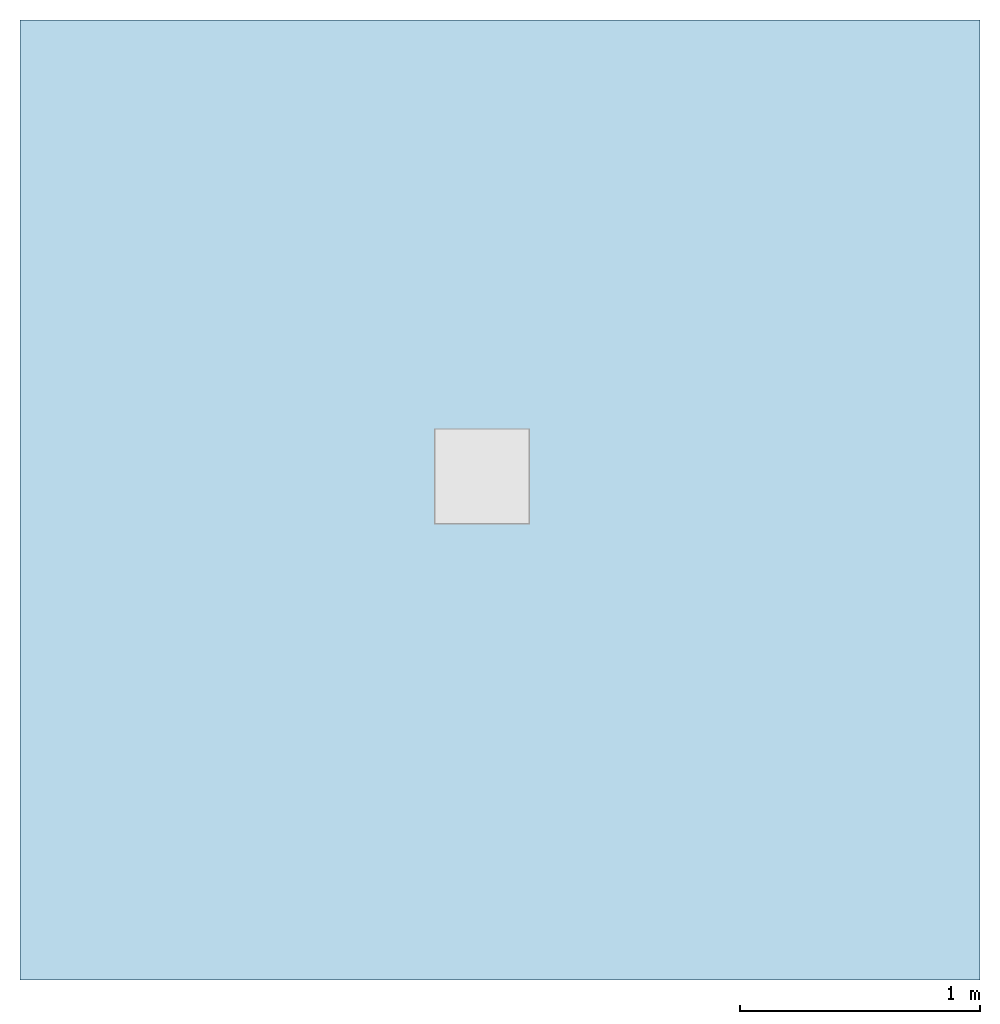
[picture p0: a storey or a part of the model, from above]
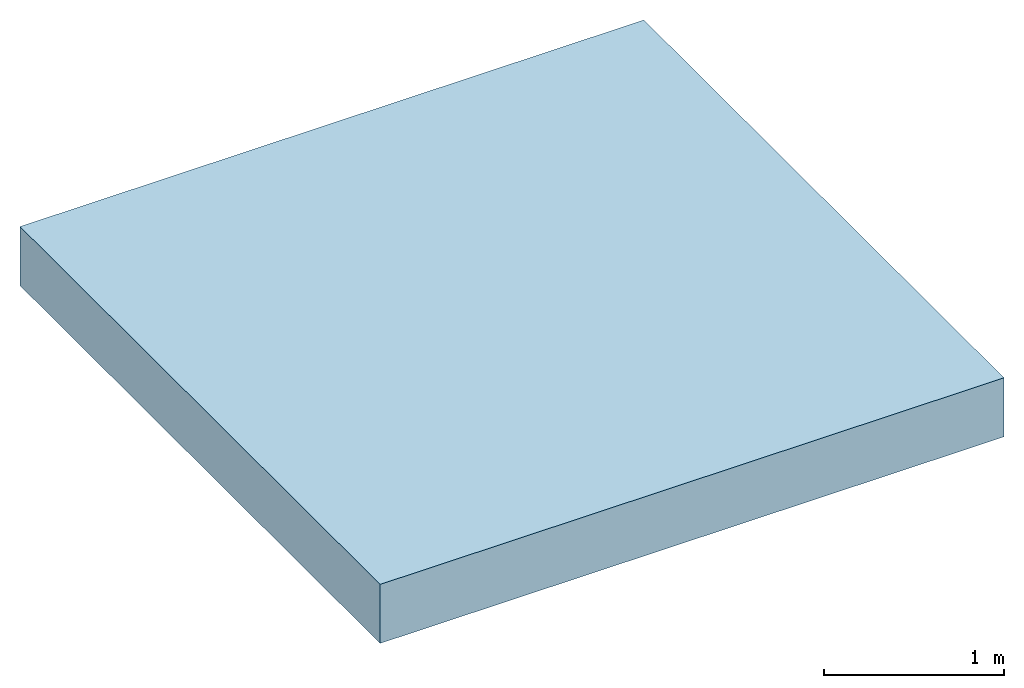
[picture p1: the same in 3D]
Properties of the parts of a building model (IFC2X3)

# File
Description: ViewDefinition [CoordinationView]
File name: Project Number
Time: 2014-06-06T11:08:49
Written by: The EXPRESS Data Manager Version 5.01.0100.02.64mod : 6 Jun 2012
Made in: 20130308_1515(x64) - Exporter 2014.0.2013.0308 - Default UI
Comment: STEP Physical File produced by: The EXPRESS Data Manager Version 5.01.0100.02.64mod : 6 Jun 2012 * Module: EDMstepFileFactory/EDMstandAlone * Creation date: Fri Jun 06 11:08:49 2014 * Host: IN-BLR-PC-0010 * Database: C:\Users\palleri\AppData\Local\Temp\{F4588F36-7AED-4A79-A1F6-AAA9ACE06403}\ifc * Database version: 5507 * Database creation date: Fri Jun 06 11:08:48 2014 * Schema: IFC2X3 * Model: DataRepository.ifc * Model creation date: Fri Jun 06 11:08:48 2014 * Header model: DataRepository.ifc_HeaderModel * Header model creation date: Fri Jun 06 11:08:48 2014 * EDMuser: sdai-user * EDMgroup: sdai-group * License ID and type: 5605 : Permanent license. Expiry date: * EDMstepFileFactory options: 020000

# IfcProject, Project Number
LongName: Project Name; Phase: Project Status

# IfcSite, Default
RefLatitude: 42, 21, 30, 344238; RefLongitude: -71, -3, -35, -194702; RefElevation: 0 mm

# IfcBuilding
Pset_BuildingCommon - NumberOfStoreys: 1
Other - Project Name: Project Name; Project Status: Project Status; Project Number: Project Number; Project Address: ## Street City, State Zip; Client Name: Owner; Project Issue Date: Issue Date

# IfcBuildingStorey, Level 1
LongName: Level 1; Elevation: 0 mm
Constraints - Elevation Base: Project Base Point; Elevation: 0 mm
Graphics - Line Weight: 1; Line Pattern: Center; Symbol at End 1 Default: no; Color: 0; Symbol: M_Level Head - Circle: M_Level Head - Circle; Symbol at End 2 Default: yes
Identity Data - Structural: no; Name: Level 1; Building Story: yes
Dimensions - Computation Height: 0 mm

# IfcFlowTerminal: 38803 - Access Frame - Adjustable Height - Invert Depth 75/105mm, ACO Freedeck Access Frame & Drain Duct (Accessories part 1) V1.27 - SS:38803 - Access Frame - Adjustable Height - Invert Depth 75/105mm:278221
In: Level 1
Material: Stainless Steel Grade 304
Materials and Finishes - Material: Stainless Steel Grade 304
Dimensions - Grating Start: 0 mm; Drain Duct End: -100 mm; Grating End: -20 mm; Drainage Duct – Level below FFL: 30 mm; Total Height: 105 mm; Access Frame Extension Position Height: 5000 mm; Height for Adjustable Access Frame: 105 mm; Top Void Height End: -30 mm; Base Height: 21 mm; Top Void Height Start: 2 mm
Construction - 36760_Access Grating_Mesh Grating_Stainless Steel 304: yes; 38688_Access Frame Extension_Stainless Steel_Invert Depth 75mm: no; 38686_Access Frame Extension_Stainless Steel_Invert Depth 50mm: no
Phasing - Phase Created: New Construction
Constraints - Moves With Nearby Elements: no; Level: Level: Level 1
Other - Access Frame Extension_Invert Depth 50mm: no; Fixed Access Frame Position Height: 50 mm; Access Frame Extension: no; Access Frame Extension_Invert Depth 75mm: no; Adjustable Access Frame Position Height: 105 mm; Drain Duct Vertical Height: 5000 mm; Access Frame Extension Height: 50 mm; Extension Removal Void: -2 mm; Access Frame Fixed Height: no; Drain Duct: no; Top void Size: 397 mm; Grating: yes; Access Frame Adjustable Height: yes
Identity Data - Mark: 15; Address: ACO Business Centre, Caxton Road, Bedford, MK41 0LF; Watermark1: This file is the property of ACO Technologies PLC; Fax: +44 (0)1462 851490; Website: www.acobd.com; Watermarked By: www.acobd.com; Watermark2: This file is water marked and users are prohibited to reproduce, adapt, distribute this information; Manufacturer: ACO Building Drainage; Watermarked With: BIM Manager Premium Suite; Telephone: +44 (0)1462 816666; E-mail Sales: abdcommercial@aco.co.uk; E-mail Technical: abdtechnical@aco.co.uk
Pset_ManufacturerTypeInformation - Manufacturer: ACO Building Drainage
Model Properties - Access Frame Extension Product Code 38688: Load Class A15 - Access Frame Extension - Stainless Steel 304 - Invert Depth 75mm - 1.9kg; Access Frame Extension Product Code 38687: N/A; Access Grating Product Code 36754: N/A; Access Grating Product Code 36760: Load Class A15 - Mesh Grating - 14mm x 30mm Mesh - Stainless Steel 304 - 3.5kg; Access Frame Extension Product Code 38686: Load Class A15 - Access Frame Extension - Stainless Steel 304 - Invert Depth 50mm - 1.3kg; Access Frame Extension Product Code 38685: N/A
General - Price: POA - contact ACO; Product Type: Linear Deck Drainage System; Product Range: ACO Freedeck; NBS Specification: NBS Section R10 Gravity Rainwater Drainage Systems, Subsection 365; Product Code: 38803; Channel Colour: Mid Grey; Maintenance Guidelines: X:\Electronic Literature\ABD Electronic Literature\Roof and Balcony Drainage\ACO Freedeck Brochure.pdf; Channel Material: Stainless Steel Grade 304; Channel Recycled Material Content: 60 - 70 %; Channel Recyclable: Fully recyclable; Dimensions (LxWxH): 400 x 400 x 75/105; Weight (Kg): 3.1kg; Product Standard: BS EN 1433:2002, CE marked; Product Description: ACO Freedeck Access Frame - Adjustable; Installation Guidelines: X:\Electronic Literature\ABD Electronic Literature\Roof and Balcony Drainage\ACO Freedeck Brochure.pdf; Load Class: A15

# IfcOpeningElement: Recess (2)
In: Level 1
Structural - Enable Analytical Model: no; Structural: no
Constraints - Room Bounding: yes; Height Offset From Level: 0 mm; Level: Level: Level 1; Related to Mass: no
Dimensions - Area: 16 m2; Thickness: 400 mm; Perimeter: 16000 mm; Volume: 6.38327 m3
Phasing - Phase Created: New Construction
Analytical Properties - Thermal Resistance (R): 0.382409; Absorptance: 0.1; Heat Transfer Coefficient (U): 2.615; Roughness: 1; Thermal mass: 604440
Graphics - Coarse Scale Fill Color: 0
Construction - Function: Interior; Default Thickness: 400 mm
Materials and Finishes - Structural Material: Concrete, Broom Finish

# IfcSlab: Floor:Generic Floor - 400mm, Floor:Generic Floor - 400mm:193825
In: Level 1
PredefinedType: FLOOR; Material: Concrete, Broom Finish 400 mm
Structural - Enable Analytical Model: no; Structural: no
Constraints - Room Bounding: yes; Height Offset From Level: 0 mm; Level: Level: Level 1; Related to Mass: no
Dimensions - Area: 16 m2; Thickness: 400 mm; Perimeter: 16000 mm; Volume: 6.38327 m3
Phasing - Phase Created: New Construction
Pset_SlabCommon - Reference: Generic Floor - 400mm; IsExternal: no; LoadBearing: yes; ThermalTransmittance: 2.615 kg/K/s3
Analytical Properties - Thermal Resistance (R): 0.382409; Absorptance: 0.1; Heat Transfer Coefficient (U): 2.615; Roughness: 1; Thermal mass: 604440
Graphics - Coarse Scale Fill Color: 0
Construction - Function: Interior; Default Thickness: 400 mm
Materials and Finishes - Structural Material: Concrete, Broom Finish
